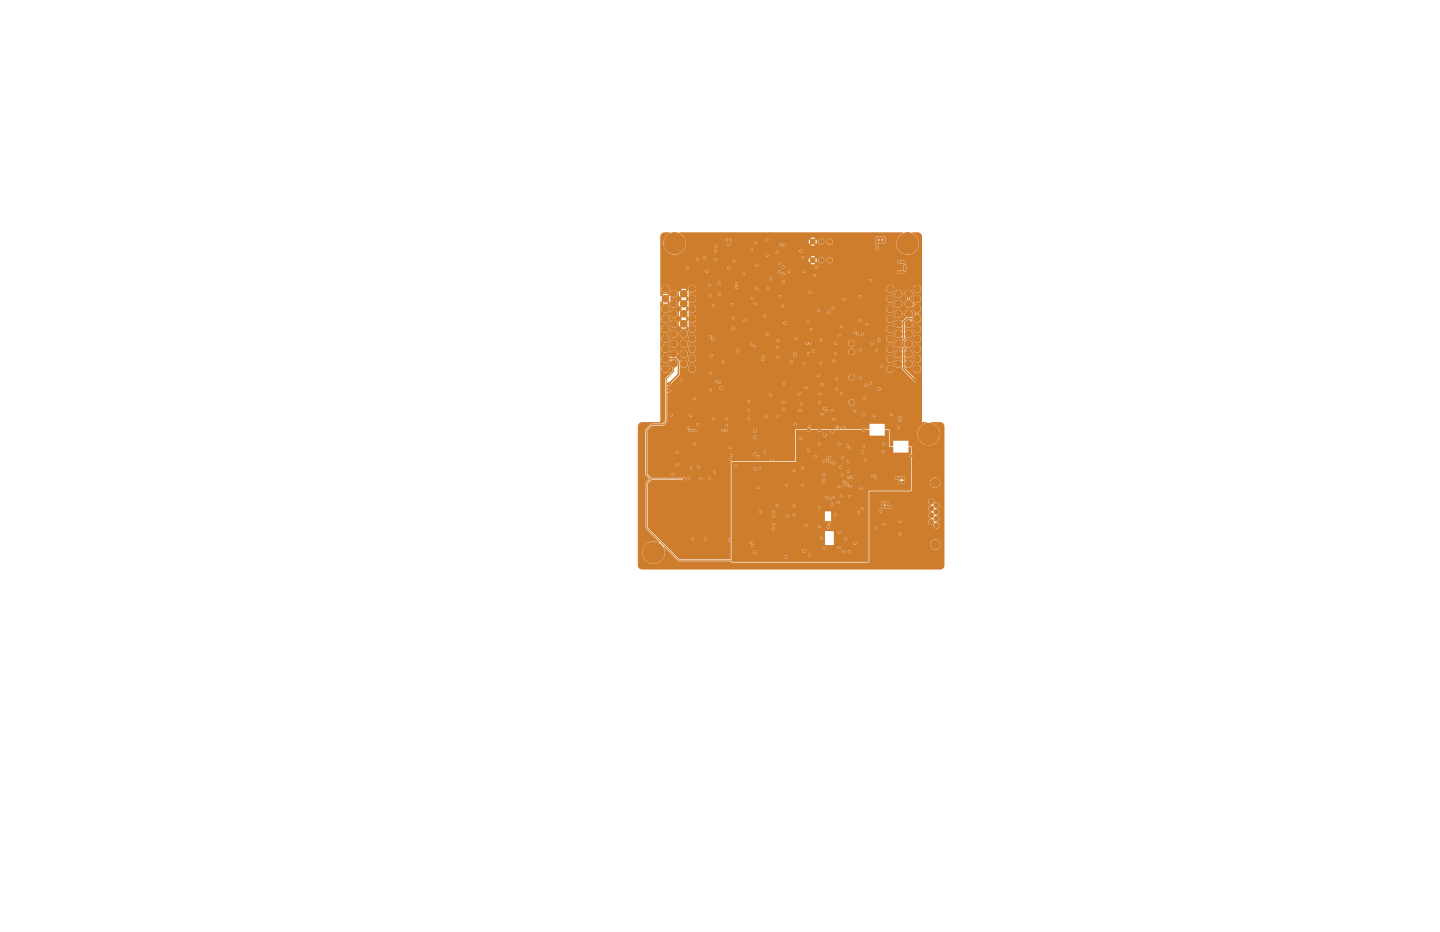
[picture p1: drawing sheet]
<svg xmlns="http://www.w3.org/2000/svg" width="432mm" height="279mm" viewBox="0 0 432 279" stroke-linecap="round" stroke-linejoin="round" font-family="sans-serif">
<g fill="#ce7d2c" stroke="#ce7d2c" stroke-width=".3">
<circle cx="255.4" cy="102.9" r=".8"/>
<circle cx="255.4" cy="105.5" r=".8"/>
<circle cx="255.4" cy="113.1" r=".8"/>
<circle cx="255.4" cy="120.7" r=".8"/>
<circle cx="202.3" cy="72.9" r="3.2"/>
<circle cx="278.5" cy="130.1" r="3.2"/>
<circle cx="196" cy="165.7" r="3.2"/>
<circle cx="207.5" cy="86.6" r="1"/>
<circle cx="207.5" cy="89.6" r="1"/>
<circle cx="207.5" cy="92.6" r="1"/>
<circle cx="207.5" cy="95.6" r="1"/>
<circle cx="207.5" cy="98.6" r="1"/>
<circle cx="207.5" cy="101.6" r="1"/>
<circle cx="207.5" cy="104.6" r="1"/>
<circle cx="207.5" cy="107.6" r="1"/>
<circle cx="207.5" cy="110.6" r="1"/>
<circle cx="205" cy="88.1" r="1"/>
<circle cx="205" cy="91.1" r="1"/>
<circle cx="205" cy="94.1" r="1"/>
<circle cx="205" cy="97.1" r="1"/>
<circle cx="205" cy="100.1" r="1"/>
<circle cx="205" cy="103.1" r="1"/>
<circle cx="205" cy="106.1" r="1"/>
<circle cx="205" cy="109.1" r="1"/>
<circle cx="202" cy="88.1" r="1"/>
<circle cx="202" cy="91.1" r="1"/>
<circle cx="202" cy="94.1" r="1"/>
<circle cx="202" cy="97.1" r="1"/>
<circle cx="202" cy="100.1" r="1"/>
<circle cx="202" cy="103.1" r="1"/>
<circle cx="202" cy="106.1" r="1"/>
<circle cx="202" cy="109.1" r="1"/>
<circle cx="199.5" cy="86.6" r="1"/>
<circle cx="199.5" cy="89.6" r="1"/>
<circle cx="199.5" cy="92.6" r="1"/>
<circle cx="199.5" cy="95.6" r="1"/>
<circle cx="199.5" cy="98.6" r="1"/>
<circle cx="199.5" cy="101.6" r="1"/>
<circle cx="199.5" cy="104.6" r="1"/>
<circle cx="199.5" cy="107.6" r="1"/>
<circle cx="199.5" cy="110.6" r="1"/>
<circle cx="243.7" cy="78" r=".72"/>
<circle cx="246.3" cy="78" r=".72"/>
<circle cx="248.8" cy="78" r=".72"/>
<circle cx="266.9" cy="110.6" r="1"/>
<circle cx="266.9" cy="107.6" r="1"/>
<circle cx="266.9" cy="104.6" r="1"/>
<circle cx="266.9" cy="101.6" r="1"/>
<circle cx="266.9" cy="98.6" r="1"/>
<circle cx="266.9" cy="95.6" r="1"/>
<circle cx="266.9" cy="92.6" r="1"/>
<circle cx="266.9" cy="89.6" r="1"/>
<circle cx="266.9" cy="86.6" r="1"/>
<circle cx="269.4" cy="109.1" r="1"/>
<circle cx="269.4" cy="106.1" r="1"/>
<circle cx="269.4" cy="103.1" r="1"/>
<circle cx="269.4" cy="100.1" r="1"/>
<circle cx="269.4" cy="97.1" r="1"/>
<circle cx="269.4" cy="94.1" r="1"/>
<circle cx="269.4" cy="91.1" r="1"/>
<circle cx="269.4" cy="88.1" r="1"/>
<circle cx="272.4" cy="109.1" r="1"/>
<circle cx="272.4" cy="106.1" r="1"/>
<circle cx="272.4" cy="103.1" r="1"/>
<circle cx="272.4" cy="100.1" r="1"/>
<circle cx="272.4" cy="97.1" r="1"/>
<circle cx="272.4" cy="94.1" r="1"/>
<circle cx="272.4" cy="91.1" r="1"/>
<circle cx="272.4" cy="88.1" r="1"/>
<circle cx="274.9" cy="110.6" r="1"/>
<circle cx="274.9" cy="107.6" r="1"/>
<circle cx="274.9" cy="104.6" r="1"/>
<circle cx="274.9" cy="101.6" r="1"/>
<circle cx="274.9" cy="98.6" r="1"/>
<circle cx="274.9" cy="95.6" r="1"/>
<circle cx="274.9" cy="92.6" r="1"/>
<circle cx="274.9" cy="89.6" r="1"/>
<circle cx="274.9" cy="86.6" r="1"/>
<circle cx="272.2" cy="72.9" r="3.2"/>
<circle cx="243.7" cy="72.4" r=".72"/>
<circle cx="246.3" cy="72.4" r=".72"/>
<circle cx="248.8" cy="72.4" r=".72"/>
<circle cx="280.8" cy="151.4" r=".72"/>
<circle cx="279.2" cy="150.4" r=".72"/>
<circle cx="279.2" cy="152.4" r=".72"/>
<circle cx="279.2" cy="154.5" r=".72"/>
<circle cx="280.8" cy="153.5" r=".72"/>
<circle cx="280.8" cy="155.5" r=".72"/>
<circle cx="280.8" cy="157.5" r=".72"/>
<circle cx="279.2" cy="156.5" r=".72"/>
<circle cx="280.4" cy="163.2" r="1.35"/>
<circle cx="280.4" cy="144.7" r="1.35"/>
<circle cx="232" cy="158.5" r=".25"/>
<circle cx="264.8" cy="135.4" r=".25"/>
<circle cx="229.2" cy="135.4" r=".25"/>
<circle cx="219.1" cy="134.2" r=".25"/>
<circle cx="257.9" cy="88.9" r=".25"/>
<circle cx="218.6" cy="73.3" r=".25"/>
<circle cx="233.8" cy="88.9" r=".25"/>
<circle cx="220.1" cy="78.3" r=".25"/>
<circle cx="263" cy="74.5" r=".38"/>
<circle cx="214.2" cy="141.5" r=".25"/>
<circle cx="253.6" cy="161.6" r=".25"/>
<circle cx="251.6" cy="100.6" r=".25"/>
<circle cx="214.5" cy="77.8" r=".25"/>
<circle cx="264" cy="72.4" r=".38"/>
<circle cx="263" cy="71.4" r=".38"/>
<circle cx="217.8" cy="129.1" r=".25"/>
<circle cx="243.2" cy="98.9" r=".25"/>
<circle cx="263" cy="73.5" r=".38"/>
<circle cx="261" cy="84.1" r=".25"/>
<circle cx="207.4" cy="140.3" r=".25"/>
<circle cx="240.7" cy="145.6" r=".25"/>
<circle cx="217.8" cy="125.5" r=".25"/>
<circle cx="251.6" cy="128.3" r=".25"/>
<circle cx="229.2" cy="94.8" r=".25"/>
<circle cx="264.8" cy="151.9" r=".38"/>
<circle cx="264" cy="71.4" r=".38"/>
<circle cx="224.4" cy="125.5" r=".25"/>
<circle cx="252.3" cy="97.8" r=".25"/>
<circle cx="270.6" cy="81.6" r=".38"/>
<circle cx="271.4" cy="79.8" r=".38"/>
<circle cx="224.4" cy="120.4" r=".25"/>
<circle cx="265" cy="71.4" r=".38"/>
<circle cx="269.4" cy="128.1" r=".25"/>
<circle cx="265.8" cy="151.9" r=".38"/>
<circle cx="247" cy="144.6" r=".25"/>
<circle cx="254.1" cy="133.7" r=".25"/>
<circle cx="245.7" cy="152.2" r=".25"/>
<circle cx="269.9" cy="156.3" r=".25"/>
<circle cx="269.6" cy="81.6" r=".38"/>
<circle cx="265" cy="72.4" r=".38"/>
<circle cx="259.1" cy="119.4" r=".3"/>
<circle cx="242.9" cy="87.7" r=".3"/>
<circle cx="265" cy="133.1" r=".25"/>
<circle cx="257.9" cy="113.3" r=".25"/>
<circle cx="208.2" cy="133.1" r=".25"/>
<circle cx="214" cy="91.5" r=".25"/>
<circle cx="231" cy="83.6" r=".25"/>
<circle cx="227.5" cy="146.1" r=".25"/>
<circle cx="270.9" cy="144.6" r=".38"/>
<circle cx="213" cy="111.8" r=".25"/>
<circle cx="246" cy="109" r=".25"/>
<circle cx="219.1" cy="137.7" r=".25"/>
<circle cx="271.4" cy="80.8" r=".38"/>
<circle cx="206.4" cy="143.6" r=".25"/>
<circle cx="216.8" cy="108.5" r=".25"/>
<circle cx="270.6" cy="78.5" r=".38"/>
<circle cx="235.1" cy="114.9" r=".25"/>
<circle cx="246.3" cy="161.3" r=".25"/>
<circle cx="273.2" cy="136.7" r=".25"/>
<circle cx="245.7" cy="120.7" r=".25"/>
<circle cx="207.1" cy="124.5" r=".25"/>
<circle cx="257.9" cy="96.1" r=".25"/>
<circle cx="260" cy="97.3" r=".25"/>
<circle cx="254.6" cy="165.4" r=".25"/>
<circle cx="247" cy="164.4" r=".25"/>
<circle cx="242.7" cy="166.4" r=".25"/>
<circle cx="231" cy="118.4" r=".25"/>
<circle cx="207.6" cy="161.6" r=".25"/>
<circle cx="249.3" cy="151.2" r=".25"/>
<circle cx="269.6" cy="78.5" r=".38"/>
<circle cx="206.1" cy="80.3" r=".25"/>
<circle cx="235.3" cy="96.8" r=".25"/>
<circle cx="236.1" cy="154.7" r=".25"/>
<circle cx="233" cy="124.8" r=".25"/>
<circle cx="250.1" cy="108.3" r=".25"/>
<circle cx="224.4" cy="123" r=".25"/>
<circle cx="253.1" cy="89.7" r=".25"/>
<circle cx="233" cy="104.2" r=".25"/>
<circle cx="210.2" cy="143.6" r=".25"/>
<circle cx="270.9" cy="143.3" r=".38"/>
<circle cx="267.3" cy="124.3" r=".25"/>
<circle cx="252.9" cy="165.4" r=".25"/>
<circle cx="221.1" cy="105.2" r=".25"/>
<circle cx="269.9" cy="144.6" r=".38"/>
<circle cx="233.3" cy="107.2" r=".25"/>
<circle cx="213" cy="116.9" r=".25"/>
<circle cx="269.9" cy="143.3" r=".38"/>
<circle cx="246.5" cy="115.4" r=".25"/>
<circle cx="254.9" cy="148.9" r=".25"/>
<circle cx="239.9" cy="123.2" r=".25"/>
<circle cx="219.8" cy="95.3" r=".25"/>
<circle cx="240.2" cy="131.4" r=".25"/>
<circle cx="211.5" cy="161.6" r=".25"/>
<circle cx="250.8" cy="113.6" r=".25"/>
<circle cx="250.1" cy="125.8" r=".25"/>
<circle cx="242.7" cy="127.8" r=".25"/>
<circle cx="265.8" cy="150.9" r=".38"/>
<circle cx="262.8" cy="158.3" r=".25"/>
<circle cx="246" cy="101.9" r=".25"/>
<circle cx="245.7" cy="133.1" r=".25"/>
<circle cx="217.8" cy="127.6" r=".25"/>
<circle cx="257.9" cy="104.9" r=".25"/>
<circle cx="203.1" cy="135.7" r=".25"/>
<circle cx="229" cy="107" r=".25"/>
<circle cx="220.9" cy="85.1" r=".25"/>
<circle cx="242.2" cy="96.3" r=".25"/>
<circle cx="230" cy="76.5" r=".25"/>
<circle cx="263" cy="72.4" r=".38"/>
<circle cx="269.9" cy="160.1" r=".25"/>
<circle cx="229.7" cy="124.8" r=".25"/>
<circle cx="208.2" cy="119.4" r=".25"/>
<circle cx="247" cy="138.2" r=".25"/>
<circle cx="266.8" cy="151.9" r=".38"/>
<circle cx="230.5" cy="86.4" r=".25"/>
<circle cx="248.1" cy="138.3" r=".25"/>
<circle cx="240.2" cy="75.2" r=".25"/>
<circle cx="248.5" cy="93.6" r=".25"/>
<circle cx="247.3" cy="122.5" r=".25"/>
<circle cx="264.8" cy="150.9" r=".38"/>
<circle cx="219.8" cy="98.3" r=".25"/>
<circle cx="212.7" cy="143.6" r=".25"/>
<circle cx="241.7" cy="157.5" r=".25"/>
<circle cx="262.3" cy="124.5" r=".25"/>
<circle cx="253.1" cy="128.3" r=".25"/>
<circle cx="268.9" cy="143.3" r=".38"/>
<circle cx="259" cy="128.8" r=".3"/>
<circle cx="264" cy="153.2" r=".25"/>
<circle cx="201.8" cy="142.3" r=".25"/>
<circle cx="259.5" cy="137.7" r=".25"/>
<circle cx="209.4" cy="140" r=".25"/>
<circle cx="235.8" cy="145.6" r=".25"/>
<circle cx="238.4" cy="127.3" r=".25"/>
<circle cx="258.2" cy="146.4" r=".25"/>
<circle cx="241.2" cy="165.1" r=".38"/>
<circle cx="217.8" cy="71.9" r=".25"/>
<circle cx="259" cy="133.9" r=".25"/>
<circle cx="256.3" cy="132.9" r=".25"/>
<circle cx="247.5" cy="166.4" r=".25"/>
<circle cx="257.9" cy="135.4" r=".25"/>
<circle cx="243.6" cy="137" r=".25"/>
<circle cx="265.3" cy="143.8" r=".38"/>
<circle cx="267.6" cy="138" r=".25"/>
<circle cx="242.9" cy="148.1" r=".25"/>
<circle cx="264.3" cy="144.8" r=".38"/>
<circle cx="260.2" cy="132.9" r=".25"/>
<circle cx="236.1" cy="159.8" r=".25"/>
<circle cx="265.3" cy="144.8" r=".38"/>
<circle cx="246.3" cy="163.1" r=".25"/>
<circle cx="255.6" cy="148.9" r=".25"/>
<circle cx="247.3" cy="151.2" r=".25"/>
<circle cx="264.3" cy="145.8" r=".38"/>
<circle cx="265.3" cy="142.8" r=".38"/>
<circle cx="250.6" cy="166.4" r=".25"/>
<circle cx="264.3" cy="142.8" r=".38"/>
<circle cx="205.1" cy="143.6" r=".25"/>
<circle cx="245.7" cy="156.3" r=".25"/>
<circle cx="266.3" cy="142.8" r=".38"/>
<circle cx="264.3" cy="143.8" r=".38"/>
<circle cx="265.3" cy="145.8" r=".38"/>
<circle cx="253.9" cy="79" r=".38"/>
<circle cx="252.9" cy="78" r=".38"/>
<circle cx="208.2" cy="139.7" r=".25"/>
<circle cx="267.3" cy="130.9" r=".25"/>
<circle cx="229.2" cy="131.6" r=".25"/>
<circle cx="218.6" cy="75.7" r=".25"/>
<circle cx="252.9" cy="79" r=".38"/>
<circle cx="252.9" cy="77" r=".38"/>
<circle cx="270.4" cy="151.9" r=".38"/>
<circle cx="226.2" cy="87.2" r=".25"/>
<circle cx="256.9" cy="76" r=".38"/>
<circle cx="241.4" cy="98.9" r=".25"/>
<circle cx="253.9" cy="80.1" r=".38"/>
<circle cx="253.1" cy="87.7" r=".25"/>
<circle cx="230.2" cy="127.6" r=".25"/>
<circle cx="264" cy="148.1" r=".38"/>
<circle cx="265" cy="148.1" r=".38"/>
<circle cx="253.9" cy="77" r=".38"/>
<circle cx="253.9" cy="78" r=".38"/>
<circle cx="253.9" cy="76" r=".38"/>
<circle cx="239.9" cy="77.5" r=".25"/>
<circle cx="226.2" cy="95" r=".25"/>
<circle cx="208.4" cy="118.4" r=".25"/>
<circle cx="252.9" cy="76" r=".38"/>
<circle cx="255.9" cy="76" r=".38"/>
<circle cx="255.9" cy="80.1" r=".38"/>
<circle cx="265" cy="149.1" r=".38"/>
<circle cx="256.9" cy="80.1" r=".38"/>
<circle cx="213.5" cy="71.4" r=".25"/>
<circle cx="269.1" cy="151.9" r=".38"/>
<circle cx="264" cy="149.1" r=".38"/>
<circle cx="254.9" cy="79" r=".38"/>
<circle cx="270.4" cy="150.7" r=".38"/>
<circle cx="208.7" cy="116.6" r=".25"/>
<circle cx="254.9" cy="80.1" r=".38"/>
<circle cx="222.1" cy="88.9" r=".25"/>
<circle cx="254.9" cy="76" r=".38"/>
<circle cx="270.4" cy="148.6" r=".38"/>
<circle cx="254.9" cy="78" r=".38"/>
<circle cx="257.9" cy="101.9" r=".25"/>
<circle cx="270.4" cy="149.7" r=".38"/>
<circle cx="252.9" cy="80.1" r=".38"/>
<circle cx="260.8" cy="124.8" r=".25"/>
<circle cx="215.3" cy="143.6" r=".25"/>
<circle cx="239.6" cy="84.6" r=".25"/>
<circle cx="218.3" cy="81.8" r=".25"/>
<circle cx="254.9" cy="77" r=".38"/>
<circle cx="219.7" cy="91.3" r=".25"/>
<circle cx="234.6" cy="91.7" r=".25"/>
<circle cx="226.4" cy="140.5" r=".38"/>
<circle cx="226.4" cy="129.1" r=".38"/>
<circle cx="216.3" cy="116.4" r=".38"/>
<circle cx="226.4" cy="131.1" r=".38"/>
<circle cx="274.2" cy="113.8" r=".38"/>
<circle cx="226.4" cy="136.2" r=".38"/>
<circle cx="226.4" cy="165.4" r=".38"/>
<circle cx="215.8" cy="114.6" r=".25"/>
<circle cx="254.6" cy="134.4" r=".25"/>
<circle cx="206.9" cy="129.1" r=".25"/>
<circle cx="208.4" cy="129.1" r=".25"/>
<circle cx="207.6" cy="129.1" r=".25"/>
<circle cx="201.3" cy="124.5" r=".25"/>
<circle cx="239.6" cy="117.9" r=".25"/>
<circle cx="251.6" cy="133.1" r=".25"/>
<circle cx="246.5" cy="124.3" r=".25"/>
<circle cx="263.5" cy="101.9" r=".3"/>
<circle cx="258.7" cy="135.4" r=".3"/>
<circle cx="240.6" cy="140.3" r=".25"/>
<circle cx="256.2" cy="123.2" r=".25"/>
<circle cx="264.3" cy="109.8" r=".25"/>
<circle cx="261.5" cy="102.9" r=".25"/>
<circle cx="265" cy="157.3" r=".25"/>
<circle cx="254.1" cy="145.1" r=".25"/>
<circle cx="250.6" cy="106" r=".25"/>
<circle cx="250.6" cy="102.9" r=".25"/>
<circle cx="245.9" cy="117.9" r=".25"/>
<circle cx="223.4" cy="96.1" r=".25"/>
<circle cx="218.6" cy="80.3" r=".25"/>
<circle cx="226.2" cy="103.9" r=".25"/>
<circle cx="242.5" cy="106" r=".25"/>
<circle cx="238.4" cy="106" r=".25"/>
<circle cx="250.8" cy="127.8" r=".25"/>
<circle cx="250.8" cy="116.6" r=".25"/>
<circle cx="238.1" cy="141" r=".25"/>
<circle cx="252.1" cy="140" r=".25"/>
<circle cx="233" cy="151.6" r=".25"/>
<circle cx="232" cy="154.7" r=".25"/>
<circle cx="249.6" cy="129.3" r=".38"/>
<circle cx="242.4" cy="128.8" r=".38"/>
<circle cx="247.3" cy="130.4" r=".38"/>
<circle cx="245.7" cy="128.8" r=".38"/>
<circle cx="259" cy="124.3" r=".38"/>
<circle cx="200.5" cy="117.1" r=".38"/>
<circle cx="252.3" cy="117.9" r=".25"/>
<circle cx="263.5" cy="116.6" r=".38"/>
<circle cx="249.5" cy="123.1" r=".25"/>
<circle cx="247.8" cy="123.2" r=".25"/>
<circle cx="204.3" cy="114.1" r=".3"/>
<circle cx="244.7" cy="80.1" r=".25"/>
<circle cx="234.1" cy="73.4" r=".25"/>
<circle cx="212.8" cy="85.6" r=".25"/>
<circle cx="212" cy="81.3" r=".25"/>
<circle cx="211.2" cy="77.3" r=".25"/>
<circle cx="213" cy="88.7" r=".25"/>
<circle cx="231.5" cy="138" r=".25"/>
<circle cx="242.5" cy="134.9" r=".25"/>
<circle cx="220.7" cy="139.6" r=".25"/>
<circle cx="250.1" cy="139" r=".25"/>
<circle cx="258.7" cy="100.3" r=".25"/>
<circle cx="240.7" cy="77.3" r=".25"/>
<circle cx="244.2" cy="82.6" r=".25"/>
<circle cx="249.8" cy="92.5" r=".25"/>
<circle cx="234.8" cy="80.1" r=".25"/>
<circle cx="233.8" cy="79" r=".25"/>
<circle cx="257.2" cy="100.3" r=".25"/>
<circle cx="236.6" cy="81.3" r=".25"/>
<circle cx="240.9" cy="81.3" r=".25"/>
<circle cx="245.5" cy="93" r=".25"/>
<circle cx="235.1" cy="73.5" r=".25"/>
<circle cx="220.9" cy="86.2" r=".25"/>
<circle cx="214.5" cy="75.2" r=".25"/>
<circle cx="225.7" cy="89.5" r=".25"/>
<circle cx="209.2" cy="77.8" r=".25"/>
<circle cx="226.4" cy="72.6" r=".25"/>
<circle cx="230" cy="71.9" r=".25"/>
<circle cx="219.1" cy="71.9" r=".25"/>
<circle cx="222.9" cy="82.3" r=".25"/>
<circle cx="214.5" cy="74" r=".25"/>
<circle cx="203.1" cy="139.2" r=".25"/>
<circle cx="249.4" cy="138.7" r=".25"/>
<circle cx="228.7" cy="107.7" r=".25"/>
<circle cx="225.4" cy="103.2" r=".25"/>
<circle cx="225.2" cy="162.6" r=".25"/>
<circle cx="218.8" cy="161.8" r=".25"/>
<circle cx="258.7" cy="152.4" r=".25"/>
<circle cx="225.7" cy="163.6" r=".25"/>
<circle cx="257.4" cy="153.7" r=".25"/>
<circle cx="232" cy="157.3" r=".25"/>
<circle cx="252.5" cy="142.3" r=".25"/>
<circle cx="247.8" cy="149.1" r=".25"/>
<circle cx="251.6" cy="159.6" r=".25"/>
<circle cx="254.4" cy="143" r=".25"/>
<circle cx="253.1" cy="144.3" r=".25"/>
<circle cx="244" cy="105.2" r=".25"/>
<circle cx="232" cy="153.5" r=".25"/>
<circle cx="228" cy="153.5" r=".25"/>
<circle cx="255.4" cy="143" r=".25"/>
<circle cx="253.4" cy="145.1" r=".25"/>
<circle cx="248.3" cy="158" r=".25"/>
<circle cx="245.7" cy="157.8" r=".25"/>
<circle cx="250.6" cy="154.3" r=".25"/>
<circle cx="248.8" cy="157" r=".25"/>
<circle cx="251.3" cy="150.7" r=".25"/>
<circle cx="249.8" cy="149.1" r=".25"/>
<circle cx="249.1" cy="149.4" r=".25"/>
<circle cx="254.4" cy="141.3" r=".25"/>
<circle cx="245.4" cy="112.6" r=".25"/>
<circle cx="238.6" cy="101.4" r=".25"/>
<circle cx="233.3" cy="102.2" r=".25"/>
<circle cx="241.9" cy="102.9" r=".25"/>
<circle cx="248.8" cy="137.2" r=".25"/>
<circle cx="259.7" cy="115.4" r=".25"/>
<circle cx="226.4" cy="91" r=".25"/>
<circle cx="234.8" cy="84.4" r=".25"/>
<circle cx="226.9" cy="86.4" r=".25"/>
<circle cx="226.9" cy="79.5" r=".25"/>
<circle cx="261" cy="114.9" r=".25"/>
<circle cx="248.1" cy="137.5" r=".25"/>
<circle cx="233.8" cy="81.5" r=".25"/>
<circle cx="233" cy="75.7" r=".25"/>
<circle cx="214.8" cy="114.3" r=".25"/>
<circle cx="216.8" cy="129.1" r=".25"/>
<circle cx="254.4" cy="138.3" r=".25"/>
<circle cx="227.7" cy="140.5" r=".25"/>
<circle cx="251.6" cy="164.1" r=".25"/>
<circle cx="256.4" cy="162.9" r=".25"/>
<circle cx="225.4" cy="74.7" r=".25"/>
<circle cx="234.8" cy="82.1" r=".25"/>
<circle cx="214" cy="125.5" r=".25"/>
<circle cx="209.2" cy="127.3" r=".25"/>
<circle cx="230" cy="100.1" r=".25"/>
<circle cx="256.4" cy="99.6" r=".25"/>
<circle cx="262.8" cy="104.9" r=".25"/>
<circle cx="240.3" cy="121.3" r=".25"/>
<circle cx="244.5" cy="136.9" r=".25"/>
<circle cx="235.1" cy="122.7" r=".25"/>
<circle cx="235.1" cy="120.7" r=".25"/>
<circle cx="261.7" cy="142.5" r=".25"/>
<circle cx="269.9" cy="125.3" r=".25"/>
<circle cx="262.5" cy="143" r=".25"/>
<circle cx="269.9" cy="126.1" r=".25"/>
<circle cx="240.9" cy="109" r=".25"/>
<circle cx="213" cy="100.9" r=".25"/>
<circle cx="213.2" cy="106.5" r=".25"/>
<circle cx="241.7" cy="116.1" r=".25"/>
<circle cx="242.9" cy="102.9" r=".25"/>
<circle cx="213.7" cy="101.6" r=".25"/>
<circle cx="215.8" cy="88.2" r=".25"/>
<circle cx="215.8" cy="84.8" r=".25"/>
<circle cx="238.1" cy="154.2" r=".25"/>
<circle cx="238.1" cy="151.7" r=".25"/>
<circle cx="200.5" cy="115.1" r=".38"/>
<circle cx="235.6" cy="166.9" r=".38"/>
<circle cx="227.5" cy="137" r=".25"/>
<circle cx="219.3" cy="136.4" r=".25"/>
<circle cx="206.3" cy="128.3" r=".25"/>
<circle cx="251.6" cy="145.8" r=".25"/>
<circle cx="252.3" cy="148.6" r=".25"/>
<circle cx="254.9" cy="145.8" r=".25"/>
<circle cx="247" cy="142.3" r=".25"/>
<circle cx="247" cy="143.8" r=".3"/>
<circle cx="252.6" cy="137.1" r=".25"/>
<circle cx="238.4" cy="106.7" r=".25"/>
<circle cx="237.4" cy="108.5" r=".25"/>
</g>
<path d="M202 109.1v2.2l-2.2 2.3v12.7l-1 1h-3.3l-1.7 1.6v13.3l1.4 1.4M195.2 143.6h9.9M195.2 143.6l-1.3 1.2v13.5l9.7 9.6h16.2" fill="none" stroke="#ce7d2c" stroke-width=".3"/>
<path d="M272.4 88.1v3h1.1l1.4 1.4M274.9 92.6v3h-3l-1 1v4.9l1.5 1.6-1.4 1.4v6.2l3.2 3.1M199.5 107.6h3.1l.9 .9v3.7l-3 2.9" fill="none" stroke="#ce7d2c" stroke-width=".51"/>
<g fill="#ce7d2c">
<path d="M219.3 138.5h19.3v-.3l8 .1a.44 .44 0 0 0 .6 .3 .44 .44 0 0 0 0-.7 .44 .44 0 0 0-.6 .3h-8v-.8h9.1l.2 1.2h1.1l.1 .3 .4 .2a.48 .48 0 0 0 .7 .3 .48 .48 0 0 0 0-.8l-.8-.4-.4 .4h-.6l.2-.4 5.4 .1a.43 .43 0 0 0 .7 .4 .43 .43 0 0 0 0-.8 .43 .43 0 0 0-.7 .3h-5.4l-.2-.3 .1-.2 10.5 .1a.44 .44 0 0 0 .7 .3 .44 .44 0 0 0 0-.8 .44 .44 0 0 0-.7 .4l-10.4-.1a.45 .45 0 0 0 .5-.1 .45 .45 0 0 0 .1-.4l3 .1a.44 .44 0 0 0 .7 .3 .44 .44 0 0 0 0-.7 .44 .44 0 0 0-.7 .3h-3l-.5-.3-.8 .3-.2 .3h-9.1v-.6h5.5a.43 .43 0 0 0 .6 .5 .43 .43 0 0 0 .1-.7 .43 .43 0 0 0-.7 .1l-5.5 .1v-1.9h3.4l.4 .5h15.8l.3 .5a.48 .48 0 0 0 .6-.5l5.3 .1a.44 .44 0 0 0 .6 .3 .44 .44 0 0 0 0-.7 .44 .44 0 0 0-.6 .3h-5.3l-.4-.4-.5 .4h-15.7a.44 .44 0 0 0 .4-.5 .44 .44 0 0 0-.4-.4 .44 .44 0 0 0-.5 .4h-3.4v-1.3h15.1l.4 .5a.54 .54 0 0 0 .3 .6 .54 .54 0 0 0 .6-.1v-.5l-.5-.3h4a.44 .44 0 0 0 .6 .5 .44 .44 0 0 0 .2-.7 .44 .44 0 0 0-.8 .1l-4 .1a.44 .44 0 0 0-.2-.6 .44 .44 0 0 0-.6 .4h-15.1v-.5h6.7l.4 .5 .4-.2 .1-.3h4.9l.4 .5 .4-.2 .1-.3 12.6 .1a.44 .44 0 0 0 .7 .3 .44 .44 0 0 0 0-.7 .44 .44 0 0 0-.7 .3h-12.6l-.4-.4-.5 .4h-4.9l-.4-.4-.5 .4h-6.7v-1.8l1.1 .1a.44 .44 0 0 0 .7 .3 .44 .44 0 0 0 0-.7 .44 .44 0 0 0-.7 .3h-1.1v-.9l8.1 .2a.56 .56 0 0 0 1 .1 .56 .56 0 0 0-.3-.9 .56 .56 0 0 0-.7 .6h-8.1l.1-1.6h3.1a.69 .69 0 0 0 .6 .6 .69 .69 0 0 0 .7-.6h2a.65 .65 0 0 0 .7 .6 .65 .65 0 0 0 .6-.6h2.7a.63 .63 0 0 0 0 .9 .63 .63 0 0 0 .8 0 .63 .63 0 0 0 .1-.8l8.4-.1a.56 .56 0 0 0 .6 .5 .56 .56 0 0 0 .5-.5l1.2 .1v1.7h4.6v-1.7l1.2-.1 .1 5.1 1.2 .1v1.7h4.6v-1.7l.6-.1 .2 2.3a.56 .56 0 0 0-.5 .5 .56 .56 0 0 0 .5 .5l-.1 9.9h-12.6l-.1 21.3-41.1-.1v-1.3l15.8 .1a.56 .56 0 0 0 .9 .2 .56 .56 0 0 0-.2-.9 .56 .56 0 0 0-.8 .6h-15.7v-.6l23 .1a.44 .44 0 0 0 .6 .3 .44 .44 0 0 0 0-.7 .44 .44 0 0 0-.6 .3h-23v-.9l6.6 .1a.56 .56 0 0 0 .7 .3 .56 .56 0 0 0 .4-.7l13.6 .2a.56 .56 0 0 0 .6 .3 .56 .56 0 0 0 .5-.4h10.7l.4 .5 .3-.1 .2-.3 .9 .1a.44 .44 0 0 0 .7 .3 .44 .44 0 0 0 0-.8 .44 .44 0 0 0-.7 .4h-.9l-.4-.5-.5 .4h-10.7a.56 .56 0 0 0-.5-.7 .56 .56 0 0 0-.6 .6h-13.6l-.6-.4-.4 .3-.1 .4h-6.6v-1.2l27.3 .1a.43 .43 0 0 0 .6 .4 .43 .43 0 0 0 .1-.7l3.9 .1a.44 .44 0 0 0 .6 .3 .44 .44 0 0 0 0-.7 .44 .44 0 0 0-.6 .3l-4.2-.1-.4 .3h-27.3v-.7l6 .1a.44 .44 0 0 0 .6 .3 .44 .44 0 0 0 0-.7 .44 .44 0 0 0-.6 .3h-6v-1.1l5.4 .2a.44 .44 0 0 0 .7 .3 .44 .44 0 0 0 0-.8 .44 .44 0 0 0-.7 .3h-5.4v-1.2l26.5 .1a.44 .44 0 0 0 .7 .3 .44 .44 0 0 0 0-.7 .44 .44 0 0 0-.7 .3h-26.5v-2.1h28.1v4.2h2.6v-.6h5.9a.44 .44 0 0 0 .6 .5 .44 .44 0 0 0 .2-.7 .44 .44 0 0 0-.7 .1l-6 .1v-1.3h3.2a.44 .44 0 0 0 .5 .5 .44 .44 0 0 0 .2-.7 .44 .44 0 0 0-.7 .1l-3.2 .1v-2h1.2a.44 .44 0 0 0 .5 .5 .44 .44 0 0 0 .2-.7 .44 .44 0 0 0-.7 .1l-1.2 .1v-.3h-2.6h-28.1v-.7l12.3 .1a.44 .44 0 0 0 .7 .3 .44 .44 0 0 0 0-.7 .44 .44 0 0 0-.7 .3h-12.3v-1.3h12.3l.4 .5 .4-.2h8.8l.4 .5 .5-.3h3.2l.4 .5 .4-.2 1.8 .1a.44 .44 0 0 0 .6 .3 .44 .44 0 0 0 0-.7 .44 .44 0 0 0-.6 .3h-1.8v-.4l-.3-.3-.5 .4h-3.2v-.3l-.4-.3-.5 .4h-8.8l-.1-.5h16.1a.44 .44 0 0 0 .5 .4 .44 .44 0 0 0 .2-.7 .44 .44 0 0 0-.7 .2l-16.4-.1-.4 .4h-12.3v-2.5h12.3l.4 .5 .3-.1 .2-.4h3.2a.44 .44 0 0 0 .5 .4 .44 .44 0 0 0 .2-.7 .44 .44 0 0 0-.7 .2l-3.2 .1-.5-.4-.4 .4h-12.3v-.5l18.4 .1a.44 .44 0 0 0 .7 .3 .44 .44 0 0 0 0-.7 .44 .44 0 0 0-.7 .3h-18.4v-.8h8.2l.4 .5 .3-.1 .2-.4h3.2a.44 .44 0 0 0 .5 .5 .44 .44 0 0 0 .3-.6h15v2.9h1.8v-2l.9 .2a.44 .44 0 0 0 .7 .3 .44 .44 0 0 0 0-.8 .44 .44 0 0 0-.7 .3h-.9v-.5h7.8a.44 .44 0 0 0 .6 .4 .44 .44 0 0 0 .1-.7 .44 .44 0 0 0-.7 .2l-7.8 .1v-.4h-16.8l-.3-.3-.5 .4h-3.2l-.4-.4-.5 .4h-8.2v-1.3h26l.4 .5 .4-.2h12.2a.44 .44 0 0 0 .5 .5 .44 .44 0 0 0 .2-.7 .44 .44 0 0 0-.7 .1l-12.2 .1v-.4l-.3-.2-.5 .3h-26v-.5h13.3l.4 .5 .3-.1 .2-.4h4.2a.44 .44 0 0 0 .6 .5 .44 .44 0 0 0 .1-.7 .44 .44 0 0 0-.7 .1l-4.2 .1-.5-.4-.4 .4h-13.3v-.5l29.6 .1a.44 .44 0 0 0 .6 .3 .44 .44 0 0 0 0-.7 .44 .44 0 0 0-.6 .3h-29.6v-.5l31.6 .1a.44 .44 0 0 0 .7 .3 .44 .44 0 0 0 0-.7 .44 .44 0 0 0-.7 .3h-31.6v-1.5h28l.4 .5 1-.3 .3 .5 .5-.2a.5 .5 0 0 0 .7-.2 .5 .5 0 0 0-.2-.7 .5 .5 0 0 0-.7 .3h-.4l-.2 .3h-.5v-.3l-.4-.3-.5 .4h-28v-.5h32.6l.4 .5 .4-.3 1.7 .2a.44 .44 0 0 0 .7 .3 .44 .44 0 0 0 0-.8 .44 .44 0 0 0-.7 .3h-1.7v-.3l-.3-.3-.5 .4h-32.6v-2.6h7.7l.4 .5 .4-.2h30a.44 .44 0 0 0 .5 .5 .44 .44 0 0 0 .2-.7 .44 .44 0 0 0-.7 .1l-30 .1 .1-.4-.4-.2-.5 .3h-7.7v-.5h16.1l.4 .5 .3-.1 .2-.4h3.9l.4 .5 .4-.2h10.2a.44 .44 0 0 0 .5 .5 .44 .44 0 0 0 .2-.8 .44 .44 0 0 0-.7 .2l-10.2 .1 .1-.4-.4-.2-.5 .3h-3.9l-.4-.3-.5 .3h-16.1v-1.8h27.2l.2 .4a.49 .49 0 0 0-.2 .7 .49 .49 0 0 0 .7 .1 .49 .49 0 0 0 .1-.6h5.4l.2 .4a.63 .63 0 0 0 .2 .7 .63 .63 0 0 0 .8 0l.6 .1a.47 .47 0 0 0 0 .7 .47 .47 0 0 0 .7-.1 .47 .47 0 0 0-.3-.7l-.3 .1a.66 .66 0 0 0-.2-.8 .66 .66 0 0 0-.8 0l-.1-.1a.44 .44 0 0 0-.3-.7 .44 .44 0 0 0-.5 .4l-5.4-.1a.49 .49 0 0 0 0-.8 .49 .49 0 0 0-.8 .3h-27.2v-.7h34.6l.4 .5 .5-.3a.48 .48 0 0 0 .8 .2 .48 .48 0 0 0-.1-.8l-.6 .3-.6-.3-.4 .4h-34.6v-.8h27.3l.4 .5 .3-.1 .1-.3h4.7l.4 .5 .4-.3h8.4l.2 .4h.5l.5 .6 5.8-.1 .3 .4h.5a.31 .31 0 0 1 .5-.1 .31 .31 0 0 1-.2 .5 .64 .64 0 0 0 .2 .9 .64 .64 0 0 0 .9-.2 .62 .62 0 0 0 .9-.1 .62 .62 0 0 0-.3-.9v-.1a.62 .62 0 0 0 .2-.9 .62 .62 0 0 0-1 0l-1.5-.2-.4 .3-.1 .4h-5.5a.53 .53 0 0 0 0-.7 .53 .53 0 0 0-.6-.2l-.4-.4-.5 .4h-8.4v-.4l-.3-.2-.5 .4h-4.7l-.3-.4-.5 .3h-27.3v-1.6h6.6l.5 .5 11.3-.1 .4 .5 .4-.3h15.4a.44 .44 0 0 0 .6 .5 .44 .44 0 0 0 .2-.7 .44 .44 0 0 0-.7 .1l-15.5 .1v-.3l-.3-.3-.5 .4h-10.9l.2-.5h.3a.44 .44 0 0 0 .5 .4 .44 .44 0 0 0 .3-.7l12.1 .2a.44 .44 0 0 0 .7 .3 .44 .44 0 0 0 0-.8l10.7 .2a.44 .44 0 0 0 .7 .3 .44 .44 0 0 0 0-.8 .44 .44 0 0 0-.7 .3h-11l-.4 .3h-12.1l-.4-.1-.4 .4-.9-.5-.4 .2-.1 .4h-6.6v-1l1 .1a.44 .44 0 0 0 .6 .3 .44 .44 0 0 0 0-.7 .44 .44 0 0 0-.6 .3h-1z"/>
<path d="M205.7 94.4l.8 .7-.1 1.1-.7 .6-.4-.4 .6-.6-.3-.2 .3-.3-.6-.6z"/>
<path d="M205.3 91.7l.4-.3 .8 .7-.1 1.1-.7 .6-.4-.4 .6-.6-.3-.2 .3-.3z"/>
<path d="M205.3 88.7l.4-.3 .8 .7-.1 1.1-.7 .6-.4-.4 .6-.6-.3-.2 .3-.3z"/>
<path d="M198.4 70l.7-.3 1.8 .1a3.4 3.4 0 0 0-1.5 4.8 3.4 3.4 0 0 0 4.9 1.1l28.3 .1a.44 .44 0 0 0 .7 .3 .44 .44 0 0 0 0-.7 .44 .44 0 0 0-.7 .3h-28.3l.6-.5h9.2a.44 .44 0 0 0 .5 .4 .44 .44 0 0 0 .2-.7 .44 .44 0 0 0-.7 .2l-9.2 .1 .3-.5h19.7l.4 .5h14.4a.44 .44 0 0 0 .6 .4 .44 .44 0 0 0 .2-.7 .44 .44 0 0 0-.7 .2l-14.3 .1a.44 .44 0 0 0 .2-.8 .44 .44 0 0 0-.8 .3h-19.7l.3-.8h8.6a.44 .44 0 0 0 .5 .5 .44 .44 0 0 0 .2-.7 .44 .44 0 0 0-.7 .1l-8.6 .1 .2-.7h12.4l.4 .5 .5-.4h14.6l.4 .5 .5-.2a.48 .48 0 0 0 .7 .2 .48 .48 0 0 0 0-.7l-.6 .2-.6-.3-.4 .3h-14.6l-.1-.3-.4-.2-.4 .4h-12.4v-.6l20.3 .1a.44 .44 0 0 0 .7 .3 .44 .44 0 0 0 0-.7 .44 .44 0 0 0-.7 .3h-20.3l-.2-.7h11.9l.3 .5 .4-.2 .1-.3h.4l.4 .5 .3-.1 .2-.4h10.1l.3 .5 12.6-.1 .2 .8 .6-.6 .4 .3-.7 .7 .6 .2 .8-.2-.6-.7 .3-.3 .6 .6 .2-.7h.5v.1a.9 .9 0 0 0 .9 .8 .9 .9 0 0 0 .8-.9h.8v.1a.9 .9 0 0 0 1.4 .7 .9 .9 0 0 0 0-1.5 .9 .9 0 0 0-1.4 .7h-.8v-.2a.9 .9 0 0 0-.9-.7 .9 .9 0 0 0-.8 .9h-.5l-.2-.6-.6 .6-.3-.4 .5-.5h18.2l.2 .4-.2 .5 .2 .5-.2 .6 .2 .4a.61 .61 0 0 0-.1 .9 .61 .61 0 0 0 .9 0 .61 .61 0 0 0-.1-.9l.2-.4-.2-.7 .7 .2 .4-.2a.65 .65 0 0 0 1 0 .65 .65 0 0 0-.1-1 .63 .63 0 0 0-.1-.8 .63 .63 0 0 0-.9 0l-.3-.1-.5 .1a.66 .66 0 0 0-.7-.1 .66 .66 0 0 0-.4 .6h-18.2l-.7-.3-.6 .2 .7 .6-.4 .4-.6-.6-.2 .5h-12.3a.44 .44 0 0 0 .1-.7 .44 .44 0 0 0-.7 .3h-10.1l-.4-.4-.5 .4h-.4l-.3-.4-.5 .4h-11.9l-.7-1.2-1.1-.9h67.1a3.4 3.4 0 0 0-1.3 5.2 3.4 3.4 0 0 0 5.4 0 3.4 3.4 0 0 0-1.4-5.2l2.1-.1 .6 .5 .3 .7v55.4l.2 .2 1.2 .2a3.4 3.4 0 0 0-2.5 4.8 3.4 3.4 0 0 0 5.3 1 3.4 3.4 0 0 0-.7-5.5l-.9-.4h3l.9 .5 .2 .7v41.7a1.27 1.27 0 0 1-1.3 1.2h-89.8a1.27 1.27 0 0 1-.8-1.2v-4h1.3a3.4 3.4 0 0 0 4.2 3.4 3.4 3.4 0 0 0 2.2-5l4.5 4.3h15.5l.5 .4h40.8l.4-.3v-5.2h18.2v.3a1.53 1.53 0 0 0 2.3 1.1 1.53 1.53 0 0 0 0-2.6 1.53 1.53 0 0 0-2.3 1.2h-18.2v-3.1l8.7 .1a.44 .44 0 0 0 .7 .3 .44 .44 0 0 0 0-.7 .44 .44 0 0 0-.7 .3h-8.7v-1.8l1.6 .1a.44 .44 0 0 0 .7 .4 .44 .44 0 0 0 0-.8 .44 .44 0 0 0-.7 .3h-1.6v-1l3.9 .1a.44 .44 0 0 0 .7 .3 .44 .44 0 0 0 0-.7 .44 .44 0 0 0-.7 .3h-3.9v-1l8.7 .1a.44 .44 0 0 0 .7 .3 .44 .44 0 0 0 0-.7 .44 .44 0 0 0-.7 .3h-8.7v-3l2.9 .1a.44 .44 0 0 0 .7 .3 .44 .44 0 0 0 0-.8 .44 .44 0 0 0-.7 .4h-2.9v-2.2h3.5l.2 .3a.69 .69 0 0 0 0 1 .69 .69 0 0 0 1 0l.3 .2 .5-.2a.63 .63 0 0 0 1 .2 .63 .63 0 0 0 0-1 .63 .63 0 0 0-.9 .1l-.1-.1a.69 .69 0 0 0 0-1 .69 .69 0 0 0-1 .1l-.6-.2-.4 .6h-3.5v-.7h17.6l.2 .7 .7 .5a1.03 1.03 0 0 0-.8 1 1.03 1.03 0 0 0 .8 1 1.03 1.03 0 0 0-.8 1 1.03 1.03 0 0 0 .8 1 .99 .99 0 0 0-.8 1.3 .99 .99 0 0 0 1.5 .6 .94 .94 0 0 0 .8 1 .94 .94 0 0 0 1-.9 .94 .94 0 0 0-.9-1 1.07 1.07 0 0 0 .9-1 1.07 1.07 0 0 0-.9-1.1 1.03 1.03 0 0 0 .9-1 1.03 1.03 0 0 0-.9-1 .99 .99 0 0 0 .8-1.3 .99 .99 0 0 0-1.4-.5 .92 .92 0 0 0-.8-1.1 .92 .92 0 0 0-1.1 .8h-17.6v-2.9l12.4-.1 .3-.3v-2.4h5.5v.2a1.53 1.53 0 0 0 2.3 1.2 1.53 1.53 0 0 0 0-2.6 1.53 1.53 0 0 0-2.3 1.2h-5.5v-7.4a.68 .68 0 0 0 0-1l-.1-2.3-.9-.3v-1.5h-4.6v1.6l-1-.1-.1-4.7-.2-.2-1.1-.1-.1-.6h3.6a.44 .44 0 0 0 .6 .5 .44 .44 0 0 0 .2-.7 .44 .44 0 0 0-.7 .1l-3.7 .1v-1h-4.6v1.6h-1.2a.7 .7 0 0 0-1.1 0h-4.8a.5 .5 0 0 0-.5-.7 .5 .5 0 0 0-.4 .7h-.7a.66 .66 0 0 0-.7-.8 .47 .47 0 0 0-.7-.3 .47 .47 0 0 0-.2 .7 .47 .47 0 0 0 .7 .1v.3l-1.3 .2-3.4-.2a.75 .75 0 0 0-1.3 0h-2.1l-.2-.4a.45 .45 0 0 0 .3-.6 .45 .45 0 0 0-.7-.1 .45 .45 0 0 0 0 .6l-.6 .5h-3l-.3 .2-.1 9.4-6.4 .1a.51 .51 0 0 0-.5-.8 .51 .51 0 0 0-.4 .8h-11.6l-.3 .2-.1 22.9a.5 .5 0 0 0-.7 .4 .5 .5 0 0 0 .7 .5v5.3h-15.3l-6.2-6.1h9.6l.4 .5 .3-.1 .2-.4 2.9 .1a.44 .44 0 0 0 .7 .4 .44 .44 0 0 0 0-.8 .44 .44 0 0 0-.7 .3h-2.9l-.4-.3-.5 .3h-9.6l-3.4-3.4v-13.1l1.2-1.1 9.8 .1 .3-.5h.4l.2 .4 .3 .1 .4-.5h3l.1 .4 .3 .1 .4-.5 1.7 .1a.44 .44 0 0 0 .7 .3 .44 .44 0 0 0 0-.7 .44 .44 0 0 0-.7 .3h-1.7l-.4-.4-.4 .4h-3l-.4-.4-.5 .4h-.4l-.3-.4-9.8 .2-1.1-1.1 7.1 .1a.44 .44 0 0 0 .6 .4 .44 .44 0 0 0 0-.8 .44 .44 0 0 0-.6 .3h-7.1l-.2-.7h19.7a.44 .44 0 0 0 .6 .4 .44 .44 0 0 0 .2-.7 .44 .44 0 0 0-.8 .2l-19.7 .1v-1.3h12.9a.43 .43 0 0 0 .5 .5 .43 .43 0 0 0 .2-.8l1.3 .2a.44 .44 0 0 0 .7 .3 .44 .44 0 0 0 0-.8 .44 .44 0 0 0-.7 .3l-1.7-.1-.3 .4h-12.9v-1l8.5 .1a.44 .44 0 0 0 .7 .3 .44 .44 0 0 0 0-.7 .44 .44 0 0 0-.7 .3h-8.5v-1.5l24.5 .1a.44 .44 0 0 0 .7 .3 .44 .44 0 0 0 0-.8 .44 .44 0 0 0-.7 .4h-24.5v-.8l32.9 .1a.44 .44 0 0 0 .7 .3 .44 .44 0 0 0 0-.7 .44 .44 0 0 0-.7 .3h-32.9v-.5l24.8 .1a.44 .44 0 0 0 .5 .4 .44 .44 0 0 0 .3-.6l6.2 .1a.56 .56 0 0 0 1 .2 .56 .56 0 0 0-.3-.9 .56 .56 0 0 0-.7 .6h-6.2l-.4-.3-.4 .4h-24.8v-.8h8.5a.43 .43 0 0 0 .6 .5 .43 .43 0 0 0 .2-.7l25.4 .1a.44 .44 0 0 0 .7 .3 .44 .44 0 0 0 0-.7 .44 .44 0 0 0-.7 .3l-25.8-.1-.4 .3h-8.5v-1.5l24.5 .1a.44 .44 0 0 0 .7 .3 .44 .44 0 0 0 0-.7 .44 .44 0 0 0-.7 .3h-24.5v-1l13.6 .1a.44 .44 0 0 0 .7 .3 .44 .44 0 0 0 0-.7 .44 .44 0 0 0-.7 .3h-13.6v-1.9l31.8 .1a.56 .56 0 0 0 1 .2 .56 .56 0 0 0-.3-.9 .56 .56 0 0 0-.7 .6h-31.8v-2.1l.8-.8h11l.2 .4 .3 .1a.6 .6 0 0 0 .3 .7 .6 .6 0 0 0 .7-.1l1.2 .1 .2-.5h7.6l.2 .5 .5-.1a.37 .37 0 0 1 .3-.2 .37 .37 0 0 1 .3 .3l.5-.3 7.7 .1a.56 .56 0 0 0 1 .2 .56 .56 0 0 0-.3-1 .56 .56 0 0 0-.7 .7h-7.7l-.3-.6-.6 .4-.6-.4-.3 .4h-7.6l-.3-.4-1.1 .1a.53 .53 0 0 1-.6-.1 .53 .53 0 0 1-.1-.5l-.5-.2-.3 .4h-11l.7-.7h3.2l.4-.4h9.5l.4 .5 .5-.2h7.8a.43 .43 0 0 0 .5 .5 .43 .43 0 0 0 .2-.8l19.8 .2a.44 .44 0 0 0 .7 .3 .44 .44 0 0 0 0-.8 .44 .44 0 0 0-.7 .3l-20.2-.1-.3 .4h-7.8v-.4l-.4-.2-.5 .3h-9.5l.9-.8v-.9h13.5l.3 .5 .4-.1 .1-.4h3l.3 .5 .4-.1 .1-.4h5.8l.4 .5 .4-.3h24.8a.44 .44 0 0 0 .6 .5 .44 .44 0 0 0 .2-.7 .44 .44 0 0 0-.7 .1l-24.9 .1-.1-.5h44.7l.2 .4a.47 .47 0 0 0-.2 .6 .47 .47 0 0 0 .7 .2 .47 .47 0 0 0 .2-.6l-.1-.1a.46 .46 0 0 0-.1-.8 .46 .46 0 0 0-.7 .3l-45-.1-.4 .4h-5.8l-.5-.4-.3 .4h-3l-.5-.4-.3 .4h-13.5v-1h.8l.3 .4h.4l.1-.4h5l.4 .4 .4-.2h21.8l.2 .4 .3 .1 .4-.5 2.4 .1a.44 .44 0 0 0 .7 .3 .44 .44 0 0 0 0-.7 .44 .44 0 0 0-.7 .3h-2.4l-.4-.4-.5 .4h-21.8v-.5h38.6l.3 .5 .5-.4h11.5l.5 .5 .6-.3h2.3a.44 .44 0 0 0 .6 .4 .44 .44 0 0 0 .2-.7l4.3 .1a.44 .44 0 0 0 .7 .3 .44 .44 0 0 0 0-.7 .44 .44 0 0 0-.7 .3l-4.7-.1-.4 .4-2.3-.2a.56 .56 0 0 0-.5-.6 .56 .56 0 0 0-.6 .6h-11.5l-.1-.3-.4-.1-.3 .3h-38.6l-.4-.1-.4 .4h-5l-.5-.4-.3 .4h-.8v-1.6h23.9l.4 .5 .4-.3 14.7 .1a.44 .44 0 0 0 .6 .3 .44 .44 0 0 0 0-.7 .44 .44 0 0 0-.6 .3h-14.7l-.2-.5 10 .1a.44 .44 0 0 0 .6 .4 .44 .44 0 0 0 .2-.7h11.4l.4 .5a.5 .5 0 0 0 .4 .6 .5 .5 0 0 0 .6-.4h.8l.4 .5 .5-.4h5.8a.44 .44 0 0 0 .6 .5 .44 .44 0 0 0 .2-.8 .44 .44 0 0 0-.7 .2l-5.9 .1-.4-.5-.5 .4h-.8l-.5-.4a.48 .48 0 0 0-.3-.6 .48 .48 0 0 0-.6 .3h-11.4l-.4-.2-.4 .4h-10.2l-.4 .3h-23.9v-1.6l39.7 .1a.44 .44 0 0 0 .7 .3 .44 .44 0 0 0 0-.7 .44 .44 0 0 0-.7 .3h-39.7v-.9h23.9l.4 .5 .4-.3h9.8l.4 .5 .3-.1 .2-.4h9.8l.2 .4 .3 .1 .4-.5h8.2a.98 .98 0 0 0 1.3 1 .98 .98 0 0 0 .4-1.6 .98 .98 0 0 0-1.6 .4l-.1 .2h-8.2l-.5-.3-.4 .3h-9.8l-.5-.3-.4 .3h-9.8v-.3l-.3-.3-.5 .4h-23.9v-1h7.6l.4 .5 .4-.2 .1-.3 50 .1a.48 .48 0 0 0 .8 .3 .48 .48 0 0 0 0-.8 .48 .48 0 0 0-.8 .4h-50l-.5-.4-.4 .4h-7.6v-1l30.5 .1a.44 .44 0 0 0 .6 .3 .44 .44 0 0 0 0-.8 .44 .44 0 0 0-.6 .4h-30.5v-.6h39.1l.3 .5 .4-.1 .1-.4h5.5l.4 .5 .3-.1 .2-.3 5.5 .1a.44 .44 0 0 0 .7 .3 .44 .44 0 0 0 0-.8 .44 .44 0 0 0-.7 .4h-5.5l-.4-.4-.5 .3h-5.5l-.3-.3-.5 .3h-39.1l.2-.1a.56 .56 0 0 0 .7-.2 .56 .56 0 0 0 0-.7l11.5 .1a.44 .44 0 0 0 .7 .4 .44 .44 0 0 0 0-.8 .44 .44 0 0 0-.7 .3h-11.5l-.4-.2h-.5v-.2l15.7 .2a.56 .56 0 0 0 .5 .3 .56 .56 0 0 0 .5-.3h33.6l.4 .5 .5-.4h11.7a.56 .56 0 0 0 .8 .4 .56 .56 0 0 0 0-.9 .56 .56 0 0 0-.8 .4l-11.7 .1-.1-.3-.4-.2-.4 .4h-33.6v-.5h24.4a.44 .44 0 0 0 .6 .4 .44 .44 0 0 0 .2-.7 .44 .44 0 0 0-.7 .2l-24.5 .1-.6-.3-.3 .2-.2 .4h-15.6v-.8h.6l.4-.3h45l.3 .5 .5-.4 12.4 .1a.44 .44 0 0 0 .6 .3 .44 .44 0 0 0 0-.7 .44 .44 0 0 0-.6 .3h-12.4l-.3-.5-.5 .4h-45l1.1-1.3h1.7l.4 .6 .5-.3h9.5l.3 .5a.73 .73 0 0 1 1.1 .2l.5-.2h18.4a.44 .44 0 0 0 .5 .5 .44 .44 0 0 0 .4-.5l25.1 .1a.44 .44 0 0 0 .6 .3 .44 .44 0 0 0 0-.7 .44 .44 0 0 0-.6 .3h-25.1l-.4-.4-.5 .4h-18.4l-.2-.5-.7 .1-.5-.5-.5 .4h-9.5a.48 .48 0 0 0-.3-.7 .48 .48 0 0 0-.6 .4h-1.7l.5-.5 47.7 .1a.44 .44 0 0 0 .7 .4 .44 .44 0 0 0 0-.8 .44 .44 0 0 0-.7 .3h-47.7l1-1h41.3l.3 .5h9.1a.98 .98 0 0 0 .8 1 .98 .98 0 0 0 1.2-.7l1.1 .1a.44 .44 0 0 0 .7 .3 .44 .44 0 0 0 0-.7 .44 .44 0 0 0-.7 .3l-1.1-.1a.98 .98 0 0 0-.9-1.1 .98 .98 0 0 0-1.1 .9h-8.8a.44 .44 0 0 0 0-.8 .44 .44 0 0 0-.6 .3h-41.3l.2-.3v-1.7h2.5l.2 .8 .8 .5h5.1a.44 .44 0 0 0 .6 .4 .44 .44 0 0 0 .2-.7 .44 .44 0 0 0-.7 .1l-5 .2 .4-.1a1.18 1.18 0 0 0 .7-1.2h57.1v.2a1.18 1.18 0 0 0 1.8 .9 1.18 1.18 0 0 0 0-2 1.18 1.18 0 0 0-1.8 .9h-57.1l-.4-.8h55.6a.44 .44 0 0 0 .5 .5 .44 .44 0 0 0 .2-.7 .44 .44 0 0 0-.7 .1l-55.6 .1a1.18 1.18 0 0 0-1.2-.2 1.18 1.18 0 0 0-.7 1h-2.5l.1-.7a1.25 1.25 0 0 0 1.4 .4 1.25 1.25 0 0 0 .8-1.2h34.3l.4 .4 .4-.1v-.3l4.3 .1a.44 .44 0 0 0 .6 .3 .44 .44 0 0 0 0-.8 .44 .44 0 0 0-.6 .4h-4.3l-.3-.4-.5 .4h-34.3a1.3 1.3 0 0 0-1-1.1 1.3 1.3 0 0 0-1.3 .5l-.8-.9h3.3v.2a1.18 1.18 0 0 0 .7 1 1.18 1.18 0 0 0 1.2-.3h8.1l.3 .5 .4-.1 .1-.4 19.7 .2a.43 .43 0 0 0 .7 .3 .43 .43 0 0 0 .1-.7l11.9 .1a.44 .44 0 0 0 .7 .3 .44 .44 0 0 0 0-.7 .44 .44 0 0 0-.7 .3l-12.3-.1-.4 .3h-19.7l-.5-.3-.3 .3h-8.1l.4-.7 19.6 .1a.49 .49 0 0 0 .7 .3 .49 .49 0 0 0 .2-.7l.2-.2h3.5l.3 .5 .5-.2h32.1v.2a1.18 1.18 0 0 0 1.8 .9 1.18 1.18 0 0 0 0-2 1.18 1.18 0 0 0-1.8 .9h-32.1a.44 .44 0 0 0-.2-.7 .44 .44 0 0 0-.6 .4h-3.5a.48 .48 0 0 0-.6-.6 .48 .48 0 0 0-.3 .7l-.2 .4h-19.6l-.3-.9-.6-.4 5 .1a.44 .44 0 0 0 .7 .3 .44 .44 0 0 0 0-.7 .44 .44 0 0 0-.7 .3h-5.4l-.6 .3-.4 .8h-3.3l-.4-.4 .5-1.1h.7a1.18 1.18 0 0 0 1.2 1.3 1.18 1.18 0 0 0 1.1-1.4h31.7l.1 .3a.5 .5 0 0 0 0 .7 .5 .5 0 0 0 .7 0 .5 .5 0 0 0 0-.7l.1-.2h3.3a.43 .43 0 0 0 .4 .5 .43 .43 0 0 0 .4-.6l7.2 .1a.44 .44 0 0 0 .7 .3 .44 .44 0 0 0 0-.7 .44 .44 0 0 0-.7 .3h-7.2l-.5-.3-.3 .4h-3.3l-.4-.5-.5 .4h-31.7a1.18 1.18 0 0 0-1.2-1 1.18 1.18 0 0 0-1.1 1.1h-.7v-.2a1.24 1.24 0 0 0-1.9-.7 1.24 1.24 0 0 0-.1 2h-.6a1.21 1.21 0 0 0-1.9-.4 1.21 1.21 0 0 0 .2 2 1.21 1.21 0 0 0 1.8-.7h.5a1.44 1.44 0 0 0 .5 2.3v.9l-2.2 2.3-.1 12.7-.8 .8h-3.3l-1.8 1.9v13.3l1.2 1.3-1.1 1.3v13.5l4.1 4.3a3.6 3.6 0 0 0-5.1 2.9h-1.3v-37.9l.3-.7 .7-.3 5.7-.2v-15.9h.4v.2a1.18 1.18 0 0 0 1.8 .9 1.18 1.18 0 0 0 0-2 1.18 1.18 0 0 0-1.8 .9h-.4v-6h.4a1.18 1.18 0 0 0 1.1 1.3 1.18 1.18 0 0 0 1.2-1.3h5.7v.2a1.18 1.18 0 0 0 .9 1 1.18 1.18 0 0 0 1.3-.6h12.1l.3 .5 .4-.1 .1-.4h22l.4 .5 .5-.2h10a.98 .98 0 0 0 1.3 1 .98 .98 0 0 0 .5-1.5h1.3l.4 .4h.3l.2-.4 3.9 .1a.44 .44 0 0 0 .7 .3 .44 .44 0 0 0 0-.7 .44 .44 0 0 0-.7 .3h-3.9l-.4-.4h7.8v.2a1.18 1.18 0 0 0 1.8 .9 1.18 1.18 0 0 0 0-2 1.18 1.18 0 0 0-1.8 .9h-7.9l-.4 .4h-1.3l-.6-.4a.98 .98 0 0 0-1.2 .9h-10l-.1-.5-.3-.1-.5 .3h-22l-.3-.3-.5 .3-12.1-.1a1.18 1.18 0 0 0-.8-1.6 1.18 1.18 0 0 0-1.4 1.1h-5.7v-.2a1.18 1.18 0 0 0-1.3-.9 1.18 1.18 0 0 0-1 1.1h-.4v-1.5h2.9a1.18 1.18 0 0 0 1.1 1.3 1.18 1.18 0 0 0 1.2-1.3h.7v.2a1.18 1.18 0 0 0 1.2 1.1 1.18 1.18 0 0 0 1.1-1.2h18.8l.3 .5h.5a.49 .49 0 0 0 .1 .6 .49 .49 0 0 0 .7-.1l6 .1a.44 .44 0 0 0 .7 .4 .44 .44 0 0 0 0-.8 .44 .44 0 0 0-.7 .3h-6l-.1-.5-.7-.1-.1-.6h15.8l.4 .5 .6-.4 .6 .3 .3-.4h6.7l.4 .5 .4-.2 .1-.4h3.4v.2a.98 .98 0 0 0 1.1 .9 .98 .98 0 0 0 .9-1h4.7l.3 .5 .5-.4h6.4a1.18 1.18 0 0 0 1.6 1.2 1.18 1.18 0 0 0 .3-2 1.18 1.18 0 0 0-1.9 .7l-6.4 .1-.4-.5-.4 .4-4.7-.1a.98 .98 0 0 0-1-.9 .98 .98 0 0 0-1 .9h-3.4l-.5-.3-.4 .4h-6.7l-.4-.4-.6 .3-.5-.3-.4 .4-16.1-.2-.4 .4h-18.8a1.18 1.18 0 0 0-1.1-1.2 1.18 1.18 0 0 0-1.2 1.1h-.7v-.2a1.18 1.18 0 0 0-1.3-.9 1.18 1.18 0 0 0-1 1.1h-2.9v-1.5h.4v.2a1.18 1.18 0 0 0 1.2 1.1 1.18 1.18 0 0 0 1.1-1.3h5.7v.2a1.18 1.18 0 0 0 .9 1 1.18 1.18 0 0 0 1.3-.6l24.3 .1a.43 .43 0 0 0 .6 .3 .43 .43 0 0 0 .1-.7h12l.1 .4 .4 .1 .3-.5h16.6a.48 .48 0 0 0 .7 .5 .48 .48 0 0 0 .1-.8h2v.2a1.18 1.18 0 0 0 1.8 .9 1.18 1.18 0 0 0 0-2 1.18 1.18 0 0 0-1.8 .9l-2.3-.1-.5 .4h-16.6l-.5-.3-.3 .3-12.4-.1-.3 .4h-24.3l.1-.6-.3-.7h4.1l.3 .5h.5a.47 .47 0 0 0 0 .6 .47 .47 0 0 0 .6 .1 .47 .47 0 0 0 .1-.7l24.2 .2a.44 .44 0 0 0 .7 .3 .44 .44 0 0 0 0-.8 .44 .44 0 0 0-.7 .3h-24.2h-.6l-.1-.7h37.9a.43 .43 0 0 0 .5 .4 .43 .43 0 0 0 .2-.7 .43 .43 0 0 0-.7 .2h-38.3l-.4 .3h-4.1a1.18 1.18 0 0 0-1.2-.3 1.18 1.18 0 0 0-.8 1h-5.7v-.2a1.18 1.18 0 0 0-1.3-.9 1.18 1.18 0 0 0-1 1.1h-.4v-1.5h2.9a1.18 1.18 0 0 0 1.1 1.3 1.18 1.18 0 0 0 1.2-1.3h.7v.2a1.18 1.18 0 0 0 1.2 1.1 1.18 1.18 0 0 0 1.1-1.2l23.4 .1a.44 .44 0 0 0 .6 .3 .44 .44 0 0 0 0-.7 .44 .44 0 0 0-.6 .3l-23.4-.1a1.18 1.18 0 0 0-1.2-1.1 1.18 1.18 0 0 0-1.1 1.1h-.7v-.2a1.18 1.18 0 0 0-1.3-.9 1.18 1.18 0 0 0-1 1.1h-2.9v-1.5h.4v.2a1.18 1.18 0 0 0 1.8 .9 1.18 1.18 0 0 0 0-2 1.18 1.18 0 0 0-1.8 .9h-.4v-1.5h2.9v.2a1.18 1.18 0 0 0 1.8 .9 1.18 1.18 0 0 0 0-2 1.18 1.18 0 0 0-1.8 .9h-2.9v-1.5h.4v.2a1.18 1.18 0 0 0 1.8 .9 1.18 1.18 0 0 0 0-2 1.18 1.18 0 0 0-1.8 .9h-.4v-1.5h2.9v.2a1.18 1.18 0 0 0 1.7 .9 1.18 1.18 0 0 0 0-2 1.18 1.18 0 0 0-1.7 .9h-2.9v-1.5h.4v.2a1.18 1.18 0 0 0 1.8 .9 1.18 1.18 0 0 0 0-2 1.18 1.18 0 0 0-1.8 .9h-.4v-2.1h.3l.6-.5 .4 .3-.6 .6a1.49 1.49 0 0 0 1.7 0l-.6-.6 .4-.3 .7 .6a1.19 1.19 0 0 0 1.1 1.7 1.19 1.19 0 0 0 1-1.7 1.37 1.37 0 0 0-2.1-.2v-1.5a1.29 1.29 0 0 0 1.5 .4 1.29 1.29 0 0 0 .8-1.2h.3l.3 .9 .6-.5 .4 .3-.6 .6 .3 .3-.3 .2 .6 .6-.4 .4-.6-.6a1.49 1.49 0 0 0 0 1.7l.6-.5 .4 .3-.6 .6 .3 .3-.3 .2 .6 .6-.4 .4-.6-.6a1.49 1.49 0 0 0 0 1.7l.6-.5 .4 .3-.6 .6 .3 .3-.3 .2 .6 .6-.4 .4-.6-.6a1.49 1.49 0 0 0 0 1.7l.6-.5 .4 .3-.6 .7a1.5 1.5 0 0 0 1.7-.1l-.6-.6 .4-.3 .7 .6a1.22 1.22 0 0 0 .3 1.4 1.22 1.22 0 0 0 1.5 .1h47.7l.3 .5h.6a.45 .45 0 0 0 .2 .7 .45 .45 0 0 0 .6-.4l.7 .1a.44 .44 0 0 0 .6 .3 .44 .44 0 0 0 0-.7 .44 .44 0 0 0-.6 .3h-.7l-.3-.4h-.6a.46 .46 0 0 0-.1-.7 .46 .46 0 0 0-.7 .3h-47.7l.5-.7h34.1a.43 .43 0 0 0 .6 .4 .43 .43 0 0 0 0-.7h22.4v.2a1.18 1.18 0 0 0 1.8 .9 1.18 1.18 0 0 0 0-2 1.18 1.18 0 0 0-1.8 .9l-22.7-.1-.3 .4h-34.1v-.5l10.7 .1a.44 .44 0 0 0 .7 .3 .44 .44 0 0 0 0-.7 .44 .44 0 0 0-.7 .3h-10.7l-.3-.5h43.5a.44 .44 0 0 0 .6 .5 .44 .44 0 0 0 .2-.8 .44 .44 0 0 0-.8 .2l-43.5 .1a1.41 1.41 0 0 0-2 0l.1-.5 53 .1a.44 .44 0 0 0 .7 .3 .44 .44 0 0 0 0-.7h8.1v.2a1.3 1.3 0 0 0 2.1 .7l-.1 1.4a1.23 1.23 0 0 0-1.7 0 1.23 1.23 0 0 0 .1 1.8 1.23 1.23 0 0 0 1.7-.2 1.51 1.51 0 0 0 .9 1.7v.9l-.7 .8-.2 1.1a1.21 1.21 0 0 0-1.8-.2 1.21 1.21 0 0 0 .1 1.8 1.21 1.21 0 0 0 1.8-.2v1.6a1.25 1.25 0 0 0-1.9-.2 1.25 1.25 0 0 0 .1 1.9 1.25 1.25 0 0 0 1.8-.3l.2 1.1 2.9 3a.58 .58 0 0 0 .6 .5 .58 .58 0 0 0 .6-.6 .58 .58 0 0 0-.6-.6l-2.7-2.7h2.3v.2a1.18 1.18 0 0 0 1.8 .9 1.18 1.18 0 0 0 0-2 1.18 1.18 0 0 0-1.8 .9h-2.3v-.6a1.24 1.24 0 0 0 1.8 0 1.24 1.24 0 0 0-.1-1.8 1.24 1.24 0 0 0-1.7 .1l-.1-.7h2.4a1.18 1.18 0 0 0 1.6 1.2 1.18 1.18 0 0 0 .3-2 1.18 1.18 0 0 0-1.9 .6l-2.4 .2 .1-.5a1.23 1.23 0 0 0 2-.4 1.23 1.23 0 0 0-1.2-1.7l-.9 .2 .2-.6h2.2a1.18 1.18 0 0 0 1.6 1.2 1.18 1.18 0 0 0 .3-2 1.18 1.18 0 0 0-1.9 .7l-2.2 .1 .4-.3a1.21 1.21 0 0 0 1.6-1.2 1.21 1.21 0 0 0-1.7-1.1l-.4-.4h2.3v.2a1.18 1.18 0 0 0 1.8 .9 1.18 1.18 0 0 0 0-2 1.18 1.18 0 0 0-1.8 .9h-2.3l-.2-.6a1.33 1.33 0 0 0 1.5 .3 1.33 1.33 0 0 0 .8-1.2 1.32 1.32 0 0 0-.9-1.1 1.32 1.32 0 0 0-1.4 .4v-.8h2.5a1.18 1.18 0 0 0 1.6 1.2 1.18 1.18 0 0 0 .3-2 1.18 1.18 0 0 0-1.9 .7l-2.5 .1v-.6a1.33 1.33 0 0 0 1.5 .3 1.33 1.33 0 0 0 .8-1.2l-.4-.9 .6-.1a1.23 1.23 0 0 0 2 .4 1.23 1.23 0 0 0-.4-2v-.7a1.23 1.23 0 0 0 .6-1.6 1.23 1.23 0 0 0-1.5-.7l-1.6-1.5-.1-.4h1v.2a1.18 1.18 0 0 0 1.8 .9 1.18 1.18 0 0 0 0-2 1.18 1.18 0 0 0-1.8 .9h-1v-.2a1.22 1.22 0 0 0 .6-1.9 1.22 1.22 0 0 0-1.9 0 1.22 1.22 0 0 0 .5 1.8v.8a1.25 1.25 0 0 0-.4 1.9 1.25 1.25 0 0 0 2-.2l.2 .4a1.29 1.29 0 0 0 .7 1.7v.7l-.7 .6h-.5a1.29 1.29 0 0 0 .2-1.5 1.29 1.29 0 0 0-1.3-.7 1.33 1.33 0 0 0-.5 2.3l-1.3 1.2a1.2 1.2 0 0 0-1.3-.5 1.2 1.2 0 0 0-.8 1.1l-8.4-.1-.4 .4h-53v-.5h28.4a.44 .44 0 0 0 .6 .4 .44 .44 0 0 0 .2-.7 .44 .44 0 0 0-.8 .2l-28.4 .1v-.5a1.29 1.29 0 0 0 2.1-.3h14.4l.3 .5 .5-.2h18a.43 .43 0 0 0 .5 .4 .43 .43 0 0 0 .2-.7l15 .1a.44 .44 0 0 0 .7 .3 .44 .44 0 0 0 0-.7 .44 .44 0 0 0-.7 .3l-15.4-.1-.3 .4h-18v-.4l-.4-.3-.4 .4h-14.4l.1-.8h10.7l.4 .5 .4-.2h45.6v.2a1.18 1.18 0 0 0 1.8 .9 1.18 1.18 0 0 0 0-2 1.18 1.18 0 0 0-1.8 .9h-45.6v-.4l-.3-.2-.5 .3h-10.7l-.3-.5h20.4a.44 .44 0 0 0 .6 .5 .44 .44 0 0 0 .2-.7 .44 .44 0 0 0-.8 .1l-20.4 .1a1.42 1.42 0 0 0-2 .1v-1.4l.4 .1a1.17 1.17 0 0 0 1.4 0h39.9l.4 .5h19.8v.2a1.18 1.18 0 0 0 1.8 .9 1.18 1.18 0 0 0 0-2 1.18 1.18 0 0 0-1.8 .9h-19.6a.44 .44 0 0 0 .1-.8 .44 .44 0 0 0-.7 .3h-39.9l.4-.5 36.5 .1a.44 .44 0 0 0 .6 .3 .44 .44 0 0 0 0-.8 .44 .44 0 0 0-.6 .4h-36.5l.1-.6h40.7l.4 .5 .3-.1 .1-.3h15.6a1.18 1.18 0 0 0 1.6 1.2 1.18 1.18 0 0 0 .3-2 1.18 1.18 0 0 0-1.9 .7l-15.6 .1-.4-.4-.4 .3h-40.7l-.3-.6-.6-.4h5.8a.44 .44 0 0 0 .5 .5 .44 .44 0 0 0 .3-.6h4.9l.3 .5 14.5-.1a.44 .44 0 0 0 .6 .5 .44 .44 0 0 0 .2-.8 .44 .44 0 0 0-.7 .2l-14.2 .1 .1-.4-.3-.4h6.2l.4 .5 .5-.4h41.4a1.18 1.18 0 0 0 1.6 1.2 1.18 1.18 0 0 0 .3-2 1.18 1.18 0 0 0-1.9 .7l-41.4 .1-.5-.5-.4 .4h-6.4l-.3 .4h-4.9l-.5-.2-.3 .3h-6.2l-.9 .5v-1.6a1.24 1.24 0 0 0 1.4 .4 1.24 1.24 0 0 0 .8-1.3h16.6l.3 .5 .5-.2h26.6l.4 .4 .4-.1v-.5h12.3v.2a1.18 1.18 0 0 0 1.8 .9 1.18 1.18 0 0 0 0-2 1.18 1.18 0 0 0-1.8 .9h-12.3l-.4-.2-.4 .4h-26.6a.44 .44 0 0 0-.3-.6 .44 .44 0 0 0-.5 .3h-16.6l-.5-.8h4.3l.4 .5 .5-.2h20a.44 .44 0 0 0 .4 .5 .44 .44 0 0 0 .4-.5l23.3 .1a.43 .43 0 0 0 .7 .3 .43 .43 0 0 0 0-.7 .43 .43 0 0 0-.7 .3h-23.3l-.3-.4-.5 .4h-20v-.4l-.4-.2-.5 .3h-4.3a1.44 1.44 0 0 0-1.8 .2l.1-.7h8.8a.44 .44 0 0 0 .6 .5 .44 .44 0 0 0 .2-.7 .44 .44 0 0 0-.7 .1l-8.9 .1-.1-.7 .2-.1 .8 .5 35.1-.2v.3a.48 .48 0 0 0 .8 .1h25v.2a1.18 1.18 0 0 0 1.8 .9 1.18 1.18 0 0 0 0-2 1.18 1.18 0 0 0-1.8 .9h-25a.48 .48 0 0 0-.2-.8 .48 .48 0 0 0-.6 .4h-34.3a1.18 1.18 0 0 0-.1-2l4.2 .1a.44 .44 0 0 0 .7 .3 .44 .44 0 0 0 0-.8 .44 .44 0 0 0-.7 .4l-4.3-.1a1.18 1.18 0 0 0-1.3 .2 1.18 1.18 0 0 0-.3 1.3l-.7 .8-.4-.4 .5-.6a1.5 1.5 0 0 0-1.6 0l.6 .6-.4 .4-.6-.6-.3 .8h-.3a1.18 1.18 0 0 0-1.5-1.1 1.18 1.18 0 0 0-.8 1.6l-.7 .8-.4-.4 .5-.6a1.5 1.5 0 0 0-1.6 0l.6 .6-.4 .4-.6-.6h-.3v-2.2h.4a1.18 1.18 0 0 0 1.6 1.2 1.18 1.18 0 0 0 .3-2 1.18 1.18 0 0 0-1.9 .6l-.4 .2v-1.7h17.3l.4 .5 .4-.2h4.3l.3 .5a.48 .48 0 0 0-.2 .7 .48 .48 0 0 0 .7 .1h5.3l.4 .4 .4-.1 .1-.3h2.7l.3 .4 .5-.3h34.9a1.18 1.18 0 0 0 1.1 1.3 1.18 1.18 0 0 0 1.2-1.3h5.7v.2a1.18 1.18 0 0 0 1.8 .9 1.18 1.18 0 0 0 0-2 1.18 1.18 0 0 0-1.8 .9h-5.7v-.2a1.18 1.18 0 0 0-1.3-.9 1.18 1.18 0 0 0-1 1.1h-34.9l-.3-.5-.5 .4h-2.7l-.4-.4-.5 .4h-5.3l.1-.4-.3-.3a.47 .47 0 0 0 .2-.8 .47 .47 0 0 0-.8 .2h-4.3a.44 .44 0 0 0-.2-.7 .44 .44 0 0 0-.6 .4h-17.3v-.5l36.4 .1a.43 .43 0 0 0 .6 .4 .43 .43 0 0 0 .1-.7l25.5 .1a.44 .44 0 0 0 .6 .3 .44 .44 0 0 0 0-.7 .44 .44 0 0 0-.6 .3l-25.8-.2-.4 .4h-36.4v-.7l32.6 .1a.44 .44 0 0 0 .6 .3 .44 .44 0 0 0 0-.8 .44 .44 0 0 0-.6 .4h-32.6v-1.3h24.5l.4 .5 .4-.3 20.5 .2a.44 .44 0 0 0 .7 .3 .44 .44 0 0 0 0-.8 .44 .44 0 0 0-.7 .3h-20.5l-.1-.5 11.2 .1a.44 .44 0 0 0 .7 .4 .44 .44 0 0 0 0-.8 .44 .44 0 0 0-.7 .3l-11.5-.1-.4 .4h-24.5v-1h13.5l.4 .5 .5-.3h21a.44 .44 0 0 0 .5 .5 .44 .44 0 0 0 .3-.7h2l.3 .5 .4-.2 .1-.3h3.5l.4 .5 28.2-.1 .4 .4 .6-.2a.71 .71 0 0 0 .8 .2 .71 .71 0 0 0 .4-.7 .67 .67 0 0 0 .6-.4 .67 .67 0 0 0-.1-.8 .58 .58 0 0 0-.1-.8 .58 .58 0 0 0-.9 .1 .58 .58 0 0 0 .3 .9 1.19 1.19 0 0 1-1.7 .7l-.3 .6-27.8-.1a.44 .44 0 0 0-.2-.7 .44 .44 0 0 0-.6 .4h-3.5l-.3-.4-.5 .4-2.5-.2-.3 .4h-21l-.1-.4-.3-.2-.5 .4h-13.5v-1h7.7l.4 .4h.3l.2-.4h11.5a.43 .43 0 0 0 .6 .4 .43 .43 0 0 0 .1-.7h15.6l.4 .5 .3-.1 .2-.4h9a.44 .44 0 0 0 .6 .5 .44 .44 0 0 0 .1-.7 .44 .44 0 0 0-.7 .1l-9 .1-.5-.4-.4 .4-15.9-.1-.4 .4h-11.5l-.5-.4-.4 .4h-7.7v-.8h28.5a.44 .44 0 0 0 .6 .5 .44 .44 0 0 0 .2-.7 .44 .44 0 0 0-.8 .1l-28.5 .1v-.5h35.4a.44 .44 0 0 0 .5 .5 .44 .44 0 0 0 .2-.8 .44 .44 0 0 0-.7 .2l-35.4 .1v-.8h21.7a.44 .44 0 0 0 .6 .5 .44 .44 0 0 0 0-.8h22.2l.2 .8 .6-.6 .4 .3-.7 .7 .6 .2 .8-.2-.6-.7 .3-.3 .6 .6 .2-.8h.5v.2a.9 .9 0 0 0 .9 .8 .9 .9 0 0 0 .8-1h.8l.1 .6a.9 .9 0 0 0 1.5 .1h19.6l.3 .5 .6-.2a.6 .6 0 0 0 1.1-.1 .6 .6 0 0 0-.7-.8l-.2 .2a.66 .66 0 0 0-.7-.2 .66 .66 0 0 0-.4 .6h-19.6a.9 .9 0 0 0-.4-1.4 .9 .9 0 0 0-1.2 .7h-.8v-.1a.9 .9 0 0 0-.9-.7 .9 .9 0 0 0-.8 .8h-.5l-.2-.5-.6 .6-.3-.4 .6-.6-.8-.2-.6 .2 .7 .6-.4 .4-.6-.6-.2 .5-22.5-.1-.3 .4h-21.7v-.5h10.7l.4 .5 .3-.1 .2-.4h4.5a.44 .44 0 0 0 .5 .5 .44 .44 0 0 0 .2-.7 .44 .44 0 0 0-.7 .1l-4.5 .1-.5-.4-.4 .4h-10.7v-.5h12.8l.3 .5 .4-.2 .1-.3h28.6a.44 .44 0 0 0 .6 .5 .44 .44 0 0 0 .2-.7 .44 .44 0 0 0-.7 .1l-28.7 .1-.5-.4-.3 .4h-12.8v-.8h31.6a.44 .44 0 0 0 .5 .5 .44 .44 0 0 0 .2-.7 .44 .44 0 0 0-.7 .1l-31.6 .1v-5.5z"/>
</g>
</svg>
